VERSION 5.7 ;
  NOWIREEXTENSIONATPIN ON ;
  DIVIDERCHAR "/" ;
  BUSBITCHARS "[]" ;
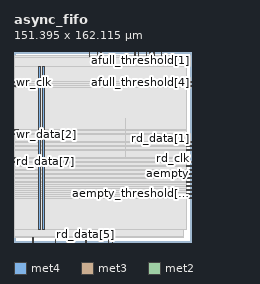
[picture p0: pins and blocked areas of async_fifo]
MACRO async_fifo
  CLASS BLOCK ;
  FOREIGN async_fifo ;
  ORIGIN 0.000 0.000 ;
  SIZE 151.395 BY 162.115 ;
  PIN VGND
    DIRECTION INOUT ;
    USE GROUND ;
    PORT
      LAYER met4 ;
        RECT 24.340 10.640 25.940 149.840 ;
    END
  END VGND
  PIN VPWR
    DIRECTION INOUT ;
    USE POWER ;
    PORT
      LAYER met4 ;
        RECT 21.040 10.640 22.640 149.840 ;
    END
  END VPWR
  PIN aempty
    DIRECTION OUTPUT ;
    USE SIGNAL ;
    ANTENNADIFFAREA 0.445500 ;
    PORT
      LAYER met3 ;
        RECT 147.395 57.840 151.395 58.440 ;
    END
  END aempty
  PIN aempty_threshold[0]
    DIRECTION INPUT ;
    USE SIGNAL ;
    ANTENNAGATEAREA 0.196500 ;
    PORT
      LAYER met3 ;
        RECT 147.395 37.440 151.395 38.040 ;
    END
  END aempty_threshold[0]
  PIN aempty_threshold[1]
    DIRECTION INPUT ;
    USE SIGNAL ;
    ANTENNAGATEAREA 0.196500 ;
    PORT
      LAYER met3 ;
        RECT 147.395 40.840 151.395 41.440 ;
    END
  END aempty_threshold[1]
  PIN aempty_threshold[2]
    DIRECTION INPUT ;
    USE SIGNAL ;
    ANTENNAGATEAREA 0.196500 ;
    PORT
      LAYER met3 ;
        RECT 147.395 44.240 151.395 44.840 ;
    END
  END aempty_threshold[2]
  PIN aempty_threshold[3]
    DIRECTION INPUT ;
    USE SIGNAL ;
    ANTENNAGATEAREA 0.196500 ;
    PORT
      LAYER met3 ;
        RECT 147.395 47.640 151.395 48.240 ;
    END
  END aempty_threshold[3]
  PIN aempty_threshold[4]
    DIRECTION INPUT ;
    USE SIGNAL ;
    ANTENNAGATEAREA 0.196500 ;
    PORT
      LAYER met3 ;
        RECT 147.395 54.440 151.395 55.040 ;
    END
  END aempty_threshold[4]
  PIN afull
    DIRECTION OUTPUT ;
    USE SIGNAL ;
    ANTENNADIFFAREA 0.445500 ;
    PORT
      LAYER met3 ;
        RECT 147.395 132.640 151.395 133.240 ;
    END
  END afull
  PIN afull_threshold[0]
    DIRECTION INPUT ;
    USE SIGNAL ;
    ANTENNAGATEAREA 0.196500 ;
    PORT
      LAYER met2 ;
        RECT 116.010 158.115 116.290 162.115 ;
    END
  END afull_threshold[0]
  PIN afull_threshold[1]
    DIRECTION INPUT ;
    USE SIGNAL ;
    ANTENNAGATEAREA 0.196500 ;
    PORT
      LAYER met2 ;
        RECT 112.790 158.115 113.070 162.115 ;
    END
  END afull_threshold[1]
  PIN afull_threshold[2]
    DIRECTION INPUT ;
    USE SIGNAL ;
    ANTENNAGATEAREA 0.196500 ;
    PORT
      LAYER met2 ;
        RECT 119.230 158.115 119.510 162.115 ;
    END
  END afull_threshold[2]
  PIN afull_threshold[3]
    DIRECTION INPUT ;
    USE SIGNAL ;
    ANTENNAGATEAREA 0.196500 ;
    PORT
      LAYER met2 ;
        RECT 125.670 158.115 125.950 162.115 ;
    END
  END afull_threshold[3]
  PIN afull_threshold[4]
    DIRECTION INPUT ;
    USE SIGNAL ;
    ANTENNAGATEAREA 0.196500 ;
    PORT
      LAYER met3 ;
        RECT 147.395 136.040 151.395 136.640 ;
    END
  END afull_threshold[4]
  PIN arst_n
    DIRECTION INPUT ;
    USE SIGNAL ;
    ANTENNAGATEAREA 0.196500 ;
    PORT
      LAYER met3 ;
        RECT 147.395 61.240 151.395 61.840 ;
    END
  END arst_n
  PIN empty
    DIRECTION OUTPUT ;
    USE SIGNAL ;
    ANTENNADIFFAREA 0.445500 ;
    PORT
      LAYER met3 ;
        RECT 147.395 78.240 151.395 78.840 ;
    END
  END empty
  PIN full
    DIRECTION OUTPUT ;
    USE SIGNAL ;
    ANTENNADIFFAREA 0.445500 ;
    PORT
      LAYER met2 ;
        RECT 106.350 158.115 106.630 162.115 ;
    END
  END full
  PIN rd_clk
    DIRECTION INPUT ;
    USE SIGNAL ;
    ANTENNAGATEAREA 0.196500 ;
    PORT
      LAYER met3 ;
        RECT 147.395 64.640 151.395 65.240 ;
    END
  END rd_clk
  PIN rd_data[0]
    DIRECTION OUTPUT ;
    USE SIGNAL ;
    ANTENNADIFFAREA 0.445500 ;
    PORT
      LAYER met2 ;
        RECT 70.930 158.115 71.210 162.115 ;
    END
  END rd_data[0]
  PIN rd_data[1]
    DIRECTION OUTPUT ;
    USE SIGNAL ;
    ANTENNADIFFAREA 0.445500 ;
    PORT
      LAYER met3 ;
        RECT 147.395 81.640 151.395 82.240 ;
    END
  END rd_data[1]
  PIN rd_data[2]
    DIRECTION OUTPUT ;
    USE SIGNAL ;
    ANTENNADIFFAREA 0.445500 ;
    PORT
      LAYER met3 ;
        RECT 0.000 95.240 4.000 95.840 ;
    END
  END rd_data[2]
  PIN rd_data[3]
    DIRECTION OUTPUT ;
    USE SIGNAL ;
    ANTENNADIFFAREA 0.445500 ;
    PORT
      LAYER met2 ;
        RECT 80.590 0.000 80.870 4.000 ;
    END
  END rd_data[3]
  PIN rd_data[4]
    DIRECTION OUTPUT ;
    USE SIGNAL ;
    ANTENNADIFFAREA 0.445500 ;
    PORT
      LAYER met3 ;
        RECT 147.395 51.040 151.395 51.640 ;
    END
  END rd_data[4]
  PIN rd_data[5]
    DIRECTION OUTPUT ;
    USE SIGNAL ;
    ANTENNADIFFAREA 0.445500 ;
    PORT
      LAYER met2 ;
        RECT 61.270 0.000 61.550 4.000 ;
    END
  END rd_data[5]
  PIN rd_data[6]
    DIRECTION OUTPUT ;
    USE SIGNAL ;
    ANTENNADIFFAREA 0.445500 ;
    PORT
      LAYER met2 ;
        RECT 64.490 158.115 64.770 162.115 ;
    END
  END rd_data[6]
  PIN rd_data[7]
    DIRECTION OUTPUT ;
    USE SIGNAL ;
    ANTENNADIFFAREA 0.445500 ;
    PORT
      LAYER met3 ;
        RECT 0.000 68.040 4.000 68.640 ;
    END
  END rd_data[7]
  PIN rd_en
    DIRECTION INPUT ;
    USE SIGNAL ;
    ANTENNAGATEAREA 0.196500 ;
    PORT
      LAYER met3 ;
        RECT 147.395 85.040 151.395 85.640 ;
    END
  END rd_en
  PIN wr_clk
    DIRECTION INPUT ;
    USE SIGNAL ;
    ANTENNAGATEAREA 0.852000 ;
    PORT
      LAYER met3 ;
        RECT 0.000 136.040 4.000 136.640 ;
    END
  END wr_clk
  PIN wr_data[0]
    DIRECTION INPUT ;
    USE SIGNAL ;
    ANTENNAGATEAREA 0.196500 ;
    PORT
      LAYER met2 ;
        RECT 74.150 158.115 74.430 162.115 ;
    END
  END wr_data[0]
  PIN wr_data[1]
    DIRECTION INPUT ;
    USE SIGNAL ;
    ANTENNAGATEAREA 0.196500 ;
    PORT
      LAYER met3 ;
        RECT 147.395 68.040 151.395 68.640 ;
    END
  END wr_data[1]
  PIN wr_data[2]
    DIRECTION INPUT ;
    USE SIGNAL ;
    ANTENNAGATEAREA 0.196500 ;
    PORT
      LAYER met3 ;
        RECT 0.000 91.840 4.000 92.440 ;
    END
  END wr_data[2]
  PIN wr_data[3]
    DIRECTION INPUT ;
    USE SIGNAL ;
    ANTENNAGATEAREA 0.196500 ;
    PORT
      LAYER met2 ;
        RECT 35.510 0.000 35.790 4.000 ;
    END
  END wr_data[3]
  PIN wr_data[4]
    DIRECTION INPUT ;
    USE SIGNAL ;
    ANTENNAGATEAREA 0.196500 ;
    PORT
      LAYER met2 ;
        RECT 83.810 0.000 84.090 4.000 ;
    END
  END wr_data[4]
  PIN wr_data[5]
    DIRECTION INPUT ;
    USE SIGNAL ;
    ANTENNAGATEAREA 0.196500 ;
    PORT
      LAYER met2 ;
        RECT 16.190 0.000 16.470 4.000 ;
    END
  END wr_data[5]
  PIN wr_data[6]
    DIRECTION INPUT ;
    USE SIGNAL ;
    ANTENNAGATEAREA 0.196500 ;
    PORT
      LAYER met3 ;
        RECT 0.000 132.640 4.000 133.240 ;
    END
  END wr_data[6]
  PIN wr_data[7]
    DIRECTION INPUT ;
    USE SIGNAL ;
    ANTENNAGATEAREA 0.196500 ;
    PORT
      LAYER met3 ;
        RECT 0.000 71.440 4.000 72.040 ;
    END
  END wr_data[7]
  PIN wr_en
    DIRECTION INPUT ;
    USE SIGNAL ;
    ANTENNAGATEAREA 0.196500 ;
    PORT
      LAYER met2 ;
        RECT 103.130 158.115 103.410 162.115 ;
    END
  END wr_en
  OBS
      LAYER nwell ;
        RECT 5.330 10.795 146.010 149.790 ;
      LAYER li1 ;
        RECT 5.520 10.795 145.820 149.685 ;
      LAYER met1 ;
        RECT 0.530 10.640 145.820 149.840 ;
      LAYER met2 ;
        RECT 0.550 157.835 64.210 158.850 ;
        RECT 65.050 157.835 70.650 158.850 ;
        RECT 71.490 157.835 73.870 158.850 ;
        RECT 74.710 157.835 102.850 158.850 ;
        RECT 103.690 157.835 106.070 158.850 ;
        RECT 106.910 157.835 112.510 158.850 ;
        RECT 113.350 157.835 115.730 158.850 ;
        RECT 116.570 157.835 118.950 158.850 ;
        RECT 119.790 157.835 125.390 158.850 ;
        RECT 126.230 157.835 144.810 158.850 ;
        RECT 0.550 4.280 144.810 157.835 ;
        RECT 0.550 4.000 15.910 4.280 ;
        RECT 16.750 4.000 35.230 4.280 ;
        RECT 36.070 4.000 60.990 4.280 ;
        RECT 61.830 4.000 80.310 4.280 ;
        RECT 81.150 4.000 83.530 4.280 ;
        RECT 84.370 4.000 144.810 4.280 ;
      LAYER met3 ;
        RECT 0.525 137.040 147.395 149.765 ;
        RECT 4.400 135.640 146.995 137.040 ;
        RECT 0.525 133.640 147.395 135.640 ;
        RECT 4.400 132.240 146.995 133.640 ;
        RECT 0.525 96.240 147.395 132.240 ;
        RECT 4.400 94.840 147.395 96.240 ;
        RECT 0.525 92.840 147.395 94.840 ;
        RECT 4.400 91.440 147.395 92.840 ;
        RECT 0.525 86.040 147.395 91.440 ;
        RECT 0.525 84.640 146.995 86.040 ;
        RECT 0.525 82.640 147.395 84.640 ;
        RECT 0.525 81.240 146.995 82.640 ;
        RECT 0.525 79.240 147.395 81.240 ;
        RECT 0.525 77.840 146.995 79.240 ;
        RECT 0.525 72.440 147.395 77.840 ;
        RECT 4.400 71.040 147.395 72.440 ;
        RECT 0.525 69.040 147.395 71.040 ;
        RECT 4.400 67.640 146.995 69.040 ;
        RECT 0.525 65.640 147.395 67.640 ;
        RECT 0.525 64.240 146.995 65.640 ;
        RECT 0.525 62.240 147.395 64.240 ;
        RECT 0.525 60.840 146.995 62.240 ;
        RECT 0.525 58.840 147.395 60.840 ;
        RECT 0.525 57.440 146.995 58.840 ;
        RECT 0.525 55.440 147.395 57.440 ;
        RECT 0.525 54.040 146.995 55.440 ;
        RECT 0.525 52.040 147.395 54.040 ;
        RECT 0.525 50.640 146.995 52.040 ;
        RECT 0.525 48.640 147.395 50.640 ;
        RECT 0.525 47.240 146.995 48.640 ;
        RECT 0.525 45.240 147.395 47.240 ;
        RECT 0.525 43.840 146.995 45.240 ;
        RECT 0.525 41.840 147.395 43.840 ;
        RECT 0.525 40.440 146.995 41.840 ;
        RECT 0.525 38.440 147.395 40.440 ;
        RECT 0.525 37.040 146.995 38.440 ;
        RECT 0.525 10.715 147.395 37.040 ;
      LAYER met4 ;
        RECT 95.055 72.255 95.385 105.225 ;
  END
END async_fifo
END LIBRARY

